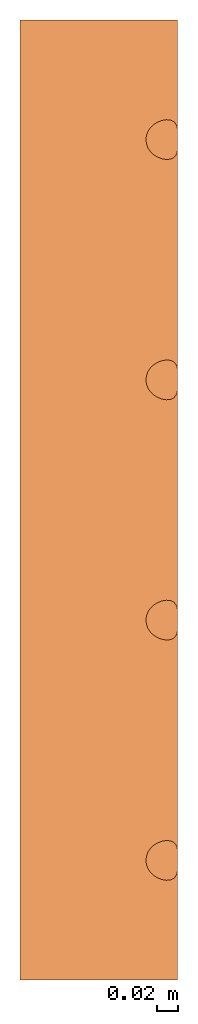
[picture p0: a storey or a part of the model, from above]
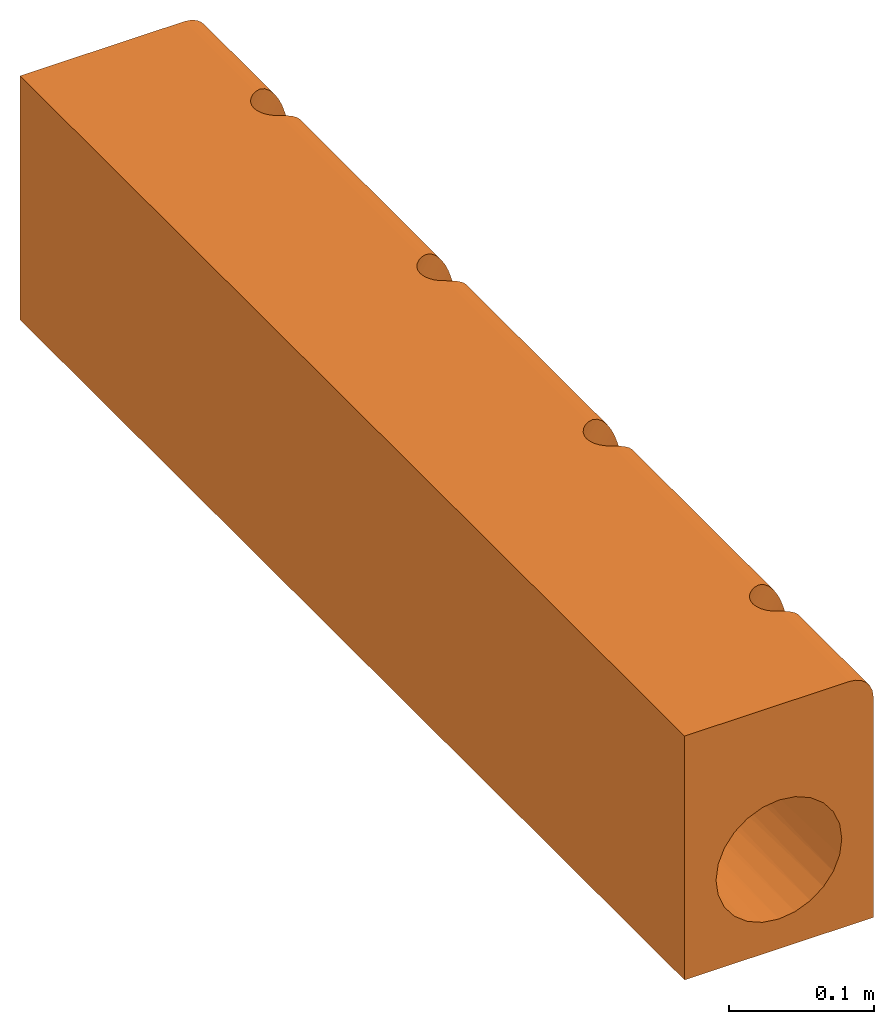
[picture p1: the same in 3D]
Properties of the parts of a building model (IFC2X3)

# File
Description: ViewDefinition [CoordinationView]
File name: 4982 - Perforated centre stone - 915mm LG.ifc
Time: 2013-09-12T12:39:06
Written by: Autodesk Revit 2013
Made in: 20120221_2030(x64)

# IfcProject, Project Number
LongName: Project Name; Phase: Project Status

# IfcSite, Default
RefLatitude: 42, 21, 30, 344238; RefLongitude: -71, -3, -35, -194702; RefElevation: 0 mm

# IfcBuilding
Pset_BuildingCommon - NumberOfStoreys: 2
Other - Client Name: Owner; Project Address: Enter address here; Project Name: Project Name; Project Number: Project Number; Project Status: Project Status; Project Issue Date: Issue Date

# IfcBuildingStorey (2)
Constraints - Elevation Base: 0
Graphics - Symbol at End 1 Default: no; Symbol: M_Level Head - Circle: M_Level Head - Circle; Line Pattern: Center; Line Weight: 1; Symbol at End 2 Default: yes; Color: 0
Identity Data - Structural: no; Building Story: yes
Dimensions - Computation Height: 0 mm
Name | LongName = Name | Elevation (mm) = Constraints, Elevation (mm)
T.O. Fnd. Wall | T.O. Fnd. Wall | -300
Level 1 | Level 1 | 0

# IfcBuildingElementProxy: 4982 - Perforated centre stone - 915mm LG, Civil-Drainage-Channel-ACO-KerbDrain-HB305 - PART 1:4982 - Perforated centre stone - 915mm LG:4982 - Perforated centre stone - 915mm LG:255899
In: T.O. Fnd. Wall
Material: ACO Polymer Concrete.
Other - Revision: 1; CreatedBy: www.aco.co.uk
General - TagNumber: 0.000000; SerialNumber: 0.000000
Materials and Finishes - Access Cover/Frame Material: N/A; Connection Pipe Material: N/A; Channel Material: Vienite® Synthetic Resin Concrete; Connection Pipe Material Colour: N/A; End Cap Material: N/A; Channel Colour: Grey; Access Cover/Frame Colour: N/A; Access Cover/Frame Finish: N/A; End Cap Colour: N/A
Phasing - Phase Created: Phase 1
Dimensions - Volume: 20463530 mm3; Void_Length: 915 mm; I/O Endcap Void depth: 6000 mm; Void_Width: 150 mm; Staright Void Depth: -180 mm
Constraints - Level: Level: Level 1; Moves With Nearby Elements: no
Pset_BuildingElementProxyCommon - Reference: 4982 - Perforated centre stone - 915mm LG
Data - Concrete Surround Volume - Load Class A 15 - D 400 - Grass or Asphalt Pavement: N/A; Drainage Slot Width: 40mm; Drainage Slot Intake area: 5026mm²/m; Load Class: A 15 - D 400; Product Dimensions: 915mm x 150mm x 205mm (LxWxH); Connection Pipe O.D: N/A; Product Standard: BS EN 1433:2002, CE marked, Kitemarked; Hydraulic Performance: http://www.aco.co.uk/download.php?id=120; Product Weight: 42.9 Kg; ACO Hydraulic Design Software: http://www.acodesign.co.uk; Concrete Surround Volume - Load Class A 15 - D 400 - Concrete Pavement: N/A; Invert Depth: 180mm; Installation - Concrete Grade: Refer to brochure; Channel C.S.A: 0.008mm²
Identity Data - Manufacturer: ACO Technologies plc - ACO Water Management Division; Address: ACO Business Park, Hitchin Road, Shefford, Bedfordshire, United Kingdom SG17 5TE; E-mail Technical: technical@aco.co.uk; OmniClass Title: Rainwater Removal; E-mail Sales: customersupport@aco.co.uk; Fax: +44 (0)1462 815895; Telephone: +44 (0)1462 816666; Product Code: 4982; Type Comments: ACO KerbDrain HB305 half battered perforated centre stone 25mm upstand 915mm long; Assembly Code: D2040; Cost: 0; Product brochure: http://www.aco.co.uk/download.php?id=120; Model: ACO KerbDrain HB305; Installation guidelines: http://www.aco.co.uk/download.php?id=120; Price: POA - contact ACO; Assembly Description: Rain Water Drainage; OmniClass Number: 23.70.50.24; Product Page URL: http://www.aco.co.uk/product_detail.php?id=3; Model Description: Combined kerb and drainage system; URL: www.aco.co.uk; Maintenance guidelines: http://www.aco.co.uk/download.php?id=120 http://www.aco.co.uk/download.php?id=120
Construction - I/O Pipe: no; KDHB305 - Access Unit: no; KDHB305 - Perforated centre stone: yes; KDHB305 - Channel unit - 250mm: no; KDHB305 - RH drop kerb: no; KDHB305 - RH Inlet/outlet end cap: no; KDHB305 - Channel unit - 500mm: no; KDHB305 - Drainable centre stone: no; KDHB305 - Channel unit - 1000mm: no; KDHB305 - Blind unit: no; KDHB305 - LH drop kerb: no; KDHB305 - Closing end cap: no; KDHB305 - Centre stone: no; KDHB305 - LH Inlet/Outlet end cap: no; KDHB305 - Flush LH dropkerb: no; KDHB305 - Flush RH dropkerb: no
Green Building Properties - End Cap Recycled Material Content: N/A; End Cap Recyclable: N/A; Channel Recycled Material Content: 20% minimum; Access Cover/Frame Recycled Material Content: N/A; Channel Recyclable: Fully recyclable; Access Cover/Frame Recyclable: N/A

# IfcOpeningElement: Recess (2)
In: Level 1
Dimensions - Thickness: 400 mm; Volume: 21181727206 mm3; Area: 53016081 mm2; Perimeter: 29157.2 mm
Structural - Enable Analytical Model: no; Structural: no
Constraints - Related to Mass: no; Level: Level: Level 1; Height Offset From Level: 0 mm; Room Bounding: yes
Phasing - Phase Created: Phase 1
Construction - Function: 0; Default Thickness: 400 mm
Graphics - Coarse Scale Fill Color: 0
Analytical Properties - Absorptance: 0.1; Roughness: 1

# IfcSlab: Floor:Generic Floor - 400mm, Floor:Generic Floor - 400mm:184025
In: Level 1
PredefinedType: FLOOR; Material: Default Floor 400 mm
Dimensions - Thickness: 400 mm; Volume: 21181727206 mm3; Area: 53016081 mm2; Perimeter: 29157.2 mm
Structural - Enable Analytical Model: no; Structural: no
Constraints - Related to Mass: no; Level: Level: Level 1; Height Offset From Level: 0 mm; Room Bounding: yes
Phasing - Phase Created: Phase 1
Pset_SlabCommon - Reference: Generic Floor - 400mm; IsExternal: no; LoadBearing: yes
Construction - Function: 0; Default Thickness: 400 mm
Graphics - Coarse Scale Fill Color: 0
Analytical Properties - Absorptance: 0.1; Roughness: 1
